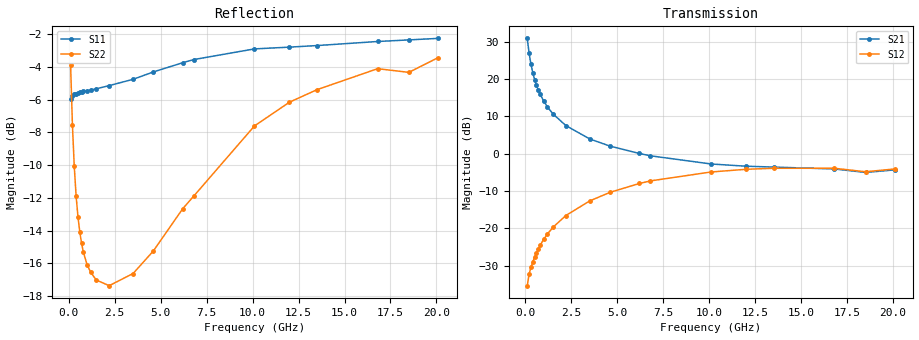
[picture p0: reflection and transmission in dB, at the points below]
!  Infineon Technologies AG
! BFR380L3 , PF131585-7, No.6, Th 09.10.01, soldered on pcb-board, measured with PP GSG850
!  Vce=6.0 V,  Ic=75.0 mA
! Common Emitter S-Parameters:  15. November 2001
#  GHz  S  MA  R  50
! f  S11  S21  S12  S22
! GHz  Mag  Ang  Mag  Ang  Mag  Ang  Mag  Ang
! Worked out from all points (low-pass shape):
!   201 points, 100 MHz to 20.1 GHz, reference 50 ohm
!   highest |S21| = 30.87 dB at 100 MHz (marker M1); lowest = -5.0 dB at 18.5 GHz (marker M2)
!   |S21| within 3 dB of the highest: start of sweep to 176.4 MHz
!   lowest |S11| = -6.0 dB at 100 MHz (marker M3), VSWR 3.02, Z = 29.7 - j39.9 ohm
!   |S11| at or under -10 dB: nowhere
!   |S22| runs from -17.4 to -3.4 dB; largest |S21 - S12| = 35
!   S11 on the Smith chart (normalised r, x): 100 MHz: 0.59, -0.80; 400 MHz: 0.32, -0.18; 2.2 GHz: 0.30, +0.21; 6.2 GHz: 0.33, +0.71; 12 GHz: 0.53, +1.45; 20.1 GHz: 1.09, +2.53
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0.1  0.5022 -90.4  34.97 134.7  0.01717 55.3  0.6408 -38.5
0.2  0.5143 -130.2  22.25 114.5  0.02443 54.7  0.4206 -52.1
0.3  0.5208 -147.3  15.8 104.8  0.03009 57.0  0.3132 -56.0
0.4  0.5232 -157.5  12.16 98.7  0.03564 59.6  0.255 -56.9
0.5  0.5266 -164.1  9.842 94.4  0.04137 62.4  0.2201 -57.0
0.6  0.5273 -169.4  8.264 91.0  0.04734 64.4  0.1978 -56.7
0.7  0.5291 -173.4  7.124 88.1  0.05317 65.9  0.1822 -56.6
0.8  0.5315 -177.0  6.257 85.5  0.05949 67.1  0.1711 -56.8
1  0.5324 177.3  5.045 81.1  0.07188 68.4  0.1568 -57.7
1.2  0.5368 172.6  4.227 77.1  0.08453 68.9  0.1486 -59.8
1.5  0.5409 166.6  3.414 71.7  0.1038 69.1  0.1409 -63.9
2.2  0.5531 154.6  2.383 60.4  0.1491 67.2  0.1354 -77.8
3.5  0.5782 135.8  1.576 42.4  0.2339 60.5  0.1475 -107.4
4.6  0.6088 122.3  1.266 29.6  0.3044 53.7  0.1728 -134.3
6.2  0.6498 105.3  1.008 14.4  0.4002 42.6  0.2327 -166.8
6.8  0.6643 99.5  0.9387 9.6  0.4333 38.0  0.2543 -177.4
10.1  0.716 74.3  0.7296 -8.6  0.5704 14.6  0.4164 138.4
12  0.725 64.5  0.6812 -15.8  0.6194 2.2  0.492 118.1
13.5  0.733 57.1  0.6635 -21.8  0.6394 -7.7  0.5374 104.8
16.8  0.7543 45.8  0.6255 -31.9  0.6393 -24.5  0.623 80.6
18.5  0.7628 44.0  0.562 -39.2  0.5741 -32.8  0.6071 74.3
20.1  0.7711 37.5  0.6088 -42.3  0.6263 -38.3  0.6737 63.0
